VERSION 5.7 ;
  NOWIREEXTENSIONATPIN ON ;
  DIVIDERCHAR "/" ;
  BUSBITCHARS "[]" ;
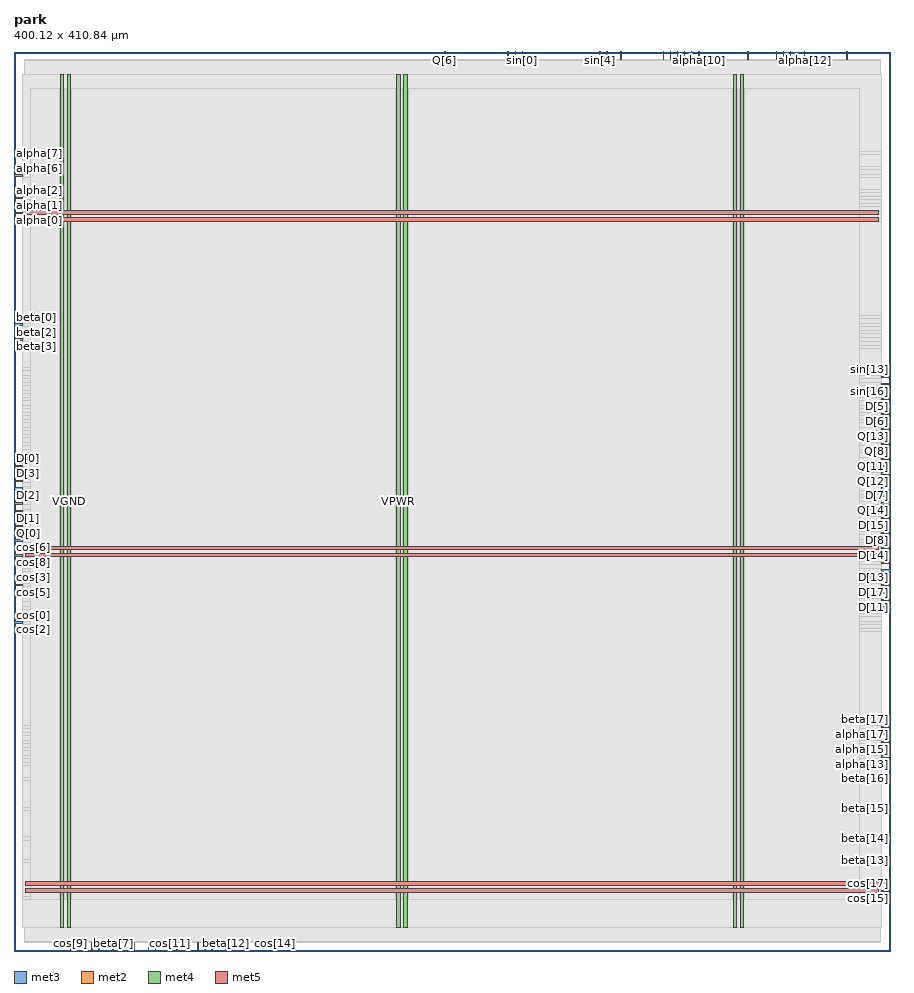
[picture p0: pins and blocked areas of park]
MACRO park
  CLASS BLOCK ;
  FOREIGN park ;
  ORIGIN 0.000 0.000 ;
  SIZE 400.120 BY 410.840 ;
  PIN D[0]
    DIRECTION OUTPUT ;
    USE SIGNAL ;
    ANTENNADIFFAREA 0.795200 ;
    PORT
      LAYER met3 ;
        RECT 0.000 224.440 4.000 225.040 ;
    END
  END D[0]
  PIN D[10]
    DIRECTION OUTPUT ;
    USE SIGNAL ;
    ANTENNADIFFAREA 0.795200 ;
    PORT
      LAYER met3 ;
        RECT 396.120 200.640 400.120 201.240 ;
    END
  END D[10]
  PIN D[11]
    DIRECTION OUTPUT ;
    USE SIGNAL ;
    ANTENNADIFFAREA 0.795200 ;
    PORT
      LAYER met3 ;
        RECT 396.120 156.440 400.120 157.040 ;
    END
  END D[11]
  PIN D[12]
    DIRECTION OUTPUT ;
    USE SIGNAL ;
    ANTENNADIFFAREA 0.445500 ;
    PORT
      LAYER met3 ;
        RECT 396.120 183.640 400.120 184.240 ;
    END
  END D[12]
  PIN D[13]
    DIRECTION OUTPUT ;
    USE SIGNAL ;
    ANTENNADIFFAREA 0.445500 ;
    PORT
      LAYER met3 ;
        RECT 396.120 170.040 400.120 170.640 ;
    END
  END D[13]
  PIN D[14]
    DIRECTION OUTPUT ;
    USE SIGNAL ;
    ANTENNADIFFAREA 0.795200 ;
    PORT
      LAYER met3 ;
        RECT 396.120 180.240 400.120 180.840 ;
    END
  END D[14]
  PIN D[15]
    DIRECTION OUTPUT ;
    USE SIGNAL ;
    ANTENNADIFFAREA 0.795200 ;
    PORT
      LAYER met3 ;
        RECT 396.120 193.840 400.120 194.440 ;
    END
  END D[15]
  PIN D[16]
    DIRECTION OUTPUT ;
    USE SIGNAL ;
    ANTENNADIFFAREA 0.795200 ;
    PORT
      LAYER met3 ;
        RECT 396.120 176.840 400.120 177.440 ;
    END
  END D[16]
  PIN D[17]
    DIRECTION OUTPUT ;
    USE SIGNAL ;
    ANTENNADIFFAREA 0.445500 ;
    PORT
      LAYER met3 ;
        RECT 396.120 163.240 400.120 163.840 ;
    END
  END D[17]
  PIN D[1]
    DIRECTION OUTPUT ;
    USE SIGNAL ;
    ANTENNADIFFAREA 0.795200 ;
    PORT
      LAYER met3 ;
        RECT 0.000 197.240 4.000 197.840 ;
    END
  END D[1]
  PIN D[2]
    DIRECTION OUTPUT ;
    USE SIGNAL ;
    ANTENNADIFFAREA 0.795200 ;
    PORT
      LAYER met3 ;
        RECT 0.000 207.440 4.000 208.040 ;
    END
  END D[2]
  PIN D[3]
    DIRECTION OUTPUT ;
    USE SIGNAL ;
    ANTENNADIFFAREA 0.795200 ;
    PORT
      LAYER met3 ;
        RECT 0.000 221.040 4.000 221.640 ;
    END
  END D[3]
  PIN D[4]
    DIRECTION OUTPUT ;
    USE SIGNAL ;
    ANTENNADIFFAREA 0.795200 ;
    PORT
      LAYER met3 ;
        RECT 0.000 210.840 4.000 211.440 ;
    END
  END D[4]
  PIN D[5]
    DIRECTION OUTPUT ;
    USE SIGNAL ;
    ANTENNADIFFAREA 0.795200 ;
    PORT
      LAYER met3 ;
        RECT 396.120 248.240 400.120 248.840 ;
    END
  END D[5]
  PIN D[6]
    DIRECTION OUTPUT ;
    USE SIGNAL ;
    ANTENNADIFFAREA 0.795200 ;
    PORT
      LAYER met3 ;
        RECT 396.120 244.840 400.120 245.440 ;
    END
  END D[6]
  PIN D[7]
    DIRECTION OUTPUT ;
    USE SIGNAL ;
    ANTENNADIFFAREA 0.795200 ;
    PORT
      LAYER met3 ;
        RECT 396.120 207.440 400.120 208.040 ;
    END
  END D[7]
  PIN D[8]
    DIRECTION OUTPUT ;
    USE SIGNAL ;
    ANTENNADIFFAREA 0.445500 ;
    PORT
      LAYER met3 ;
        RECT 396.120 190.440 400.120 191.040 ;
    END
  END D[8]
  PIN D[9]
    DIRECTION OUTPUT ;
    USE SIGNAL ;
    ANTENNADIFFAREA 0.795200 ;
    PORT
      LAYER met3 ;
        RECT 396.120 166.640 400.120 167.240 ;
    END
  END D[9]
  PIN Q[0]
    DIRECTION OUTPUT ;
    USE SIGNAL ;
    ANTENNADIFFAREA 0.795200 ;
    PORT
      LAYER met3 ;
        RECT 0.000 193.840 4.000 194.440 ;
    END
  END Q[0]
  PIN Q[10]
    DIRECTION OUTPUT ;
    USE SIGNAL ;
    ANTENNADIFFAREA 0.795200 ;
    PORT
      LAYER met3 ;
        RECT 396.120 217.640 400.120 218.240 ;
    END
  END Q[10]
  PIN Q[11]
    DIRECTION OUTPUT ;
    USE SIGNAL ;
    ANTENNADIFFAREA 0.795200 ;
    PORT
      LAYER met3 ;
        RECT 396.120 221.040 400.120 221.640 ;
    END
  END Q[11]
  PIN Q[12]
    DIRECTION OUTPUT ;
    USE SIGNAL ;
    ANTENNADIFFAREA 0.795200 ;
    PORT
      LAYER met3 ;
        RECT 396.120 214.240 400.120 214.840 ;
    END
  END Q[12]
  PIN Q[13]
    DIRECTION OUTPUT ;
    USE SIGNAL ;
    ANTENNADIFFAREA 0.445500 ;
    PORT
      LAYER met3 ;
        RECT 396.120 238.040 400.120 238.640 ;
    END
  END Q[13]
  PIN Q[14]
    DIRECTION OUTPUT ;
    USE SIGNAL ;
    ANTENNADIFFAREA 0.445500 ;
    PORT
      LAYER met3 ;
        RECT 396.120 204.040 400.120 204.640 ;
    END
  END Q[14]
  PIN Q[15]
    DIRECTION OUTPUT ;
    USE SIGNAL ;
    ANTENNADIFFAREA 0.445500 ;
    PORT
      LAYER met3 ;
        RECT 396.120 210.840 400.120 211.440 ;
    END
  END Q[15]
  PIN Q[16]
    DIRECTION OUTPUT ;
    USE SIGNAL ;
    ANTENNADIFFAREA 0.795200 ;
    PORT
      LAYER met3 ;
        RECT 396.120 187.040 400.120 187.640 ;
    END
  END Q[16]
  PIN Q[17]
    DIRECTION OUTPUT ;
    USE SIGNAL ;
    ANTENNADIFFAREA 0.795200 ;
    PORT
      LAYER met3 ;
        RECT 396.120 173.440 400.120 174.040 ;
    END
  END Q[17]
  PIN Q[1]
    DIRECTION OUTPUT ;
    USE SIGNAL ;
    ANTENNADIFFAREA 0.795200 ;
    PORT
      LAYER met3 ;
        RECT 0.000 204.040 4.000 204.640 ;
    END
  END Q[1]
  PIN Q[2]
    DIRECTION OUTPUT ;
    USE SIGNAL ;
    ANTENNADIFFAREA 0.795200 ;
    PORT
      LAYER met3 ;
        RECT 0.000 217.640 4.000 218.240 ;
    END
  END Q[2]
  PIN Q[3]
    DIRECTION OUTPUT ;
    USE SIGNAL ;
    ANTENNADIFFAREA 0.795200 ;
    PORT
      LAYER met3 ;
        RECT 0.000 200.640 4.000 201.240 ;
    END
  END Q[3]
  PIN Q[4]
    DIRECTION OUTPUT ;
    USE SIGNAL ;
    ANTENNADIFFAREA 0.795200 ;
    PORT
      LAYER met3 ;
        RECT 0.000 190.440 4.000 191.040 ;
    END
  END Q[4]
  PIN Q[5]
    DIRECTION OUTPUT ;
    USE SIGNAL ;
    ANTENNADIFFAREA 0.795200 ;
    PORT
      LAYER met3 ;
        RECT 0.000 214.240 4.000 214.840 ;
    END
  END Q[5]
  PIN Q[6]
    DIRECTION OUTPUT ;
    USE SIGNAL ;
    ANTENNADIFFAREA 0.795200 ;
    PORT
      LAYER met2 ;
        RECT 196.510 406.840 196.790 410.840 ;
    END
  END Q[6]
  PIN Q[7]
    DIRECTION OUTPUT ;
    USE SIGNAL ;
    ANTENNADIFFAREA 0.795200 ;
    PORT
      LAYER met3 ;
        RECT 396.120 241.440 400.120 242.040 ;
    END
  END Q[7]
  PIN Q[8]
    DIRECTION OUTPUT ;
    USE SIGNAL ;
    ANTENNADIFFAREA 0.445500 ;
    PORT
      LAYER met3 ;
        RECT 396.120 231.240 400.120 231.840 ;
    END
  END Q[8]
  PIN Q[9]
    DIRECTION OUTPUT ;
    USE SIGNAL ;
    ANTENNADIFFAREA 0.795200 ;
    PORT
      LAYER met3 ;
        RECT 396.120 234.640 400.120 235.240 ;
    END
  END Q[9]
  PIN VGND
    DIRECTION INOUT ;
    USE GROUND ;
    PORT
      LAYER met4 ;
        RECT 24.340 10.640 25.940 400.080 ;
    END
    PORT
      LAYER met4 ;
        RECT 177.940 10.640 179.540 400.080 ;
    END
    PORT
      LAYER met4 ;
        RECT 331.540 10.640 333.140 400.080 ;
    END
    PORT
      LAYER met5 ;
        RECT 5.280 30.030 394.460 31.630 ;
    END
    PORT
      LAYER met5 ;
        RECT 5.280 183.210 394.460 184.810 ;
    END
    PORT
      LAYER met5 ;
        RECT 5.280 336.390 394.460 337.990 ;
    END
  END VGND
  PIN VPWR
    DIRECTION INOUT ;
    USE POWER ;
    PORT
      LAYER met4 ;
        RECT 21.040 10.640 22.640 400.080 ;
    END
    PORT
      LAYER met4 ;
        RECT 174.640 10.640 176.240 400.080 ;
    END
    PORT
      LAYER met4 ;
        RECT 328.240 10.640 329.840 400.080 ;
    END
    PORT
      LAYER met5 ;
        RECT 5.280 26.730 394.460 28.330 ;
    END
    PORT
      LAYER met5 ;
        RECT 5.280 179.910 394.460 181.510 ;
    END
    PORT
      LAYER met5 ;
        RECT 5.280 333.090 394.460 334.690 ;
    END
  END VPWR
  PIN alpha[0]
    DIRECTION INPUT ;
    USE SIGNAL ;
    ANTENNAGATEAREA 0.159000 ;
    PORT
      LAYER met3 ;
        RECT 0.000 333.240 4.000 333.840 ;
    END
  END alpha[0]
  PIN alpha[10]
    DIRECTION INPUT ;
    USE SIGNAL ;
    ANTENNAGATEAREA 0.196500 ;
    PORT
      LAYER met2 ;
        RECT 312.430 406.840 312.710 410.840 ;
    END
  END alpha[10]
  PIN alpha[11]
    DIRECTION INPUT ;
    USE SIGNAL ;
    ANTENNAGATEAREA 0.196500 ;
    PORT
      LAYER met2 ;
        RECT 334.970 406.840 335.250 410.840 ;
    END
  END alpha[11]
  PIN alpha[12]
    DIRECTION INPUT ;
    USE SIGNAL ;
    ANTENNAGATEAREA 0.247500 ;
    PORT
      LAYER met2 ;
        RECT 360.730 406.840 361.010 410.840 ;
    END
  END alpha[12]
  PIN alpha[13]
    DIRECTION INPUT ;
    USE SIGNAL ;
    ANTENNAGATEAREA 0.247500 ;
    PORT
      LAYER met3 ;
        RECT 396.120 85.040 400.120 85.640 ;
    END
  END alpha[13]
  PIN alpha[14]
    DIRECTION INPUT ;
    USE SIGNAL ;
    ANTENNAGATEAREA 0.196500 ;
    PORT
      LAYER met3 ;
        RECT 396.120 88.440 400.120 89.040 ;
    END
  END alpha[14]
  PIN alpha[15]
    DIRECTION INPUT ;
    USE SIGNAL ;
    ANTENNAGATEAREA 0.196500 ;
    PORT
      LAYER met3 ;
        RECT 396.120 91.840 400.120 92.440 ;
    END
  END alpha[15]
  PIN alpha[16]
    DIRECTION INPUT ;
    USE SIGNAL ;
    ANTENNAGATEAREA 0.213000 ;
    PORT
      LAYER met3 ;
        RECT 396.120 95.240 400.120 95.840 ;
    END
  END alpha[16]
  PIN alpha[17]
    DIRECTION INPUT ;
    USE SIGNAL ;
    ANTENNAGATEAREA 0.159000 ;
    PORT
      LAYER met3 ;
        RECT 396.120 98.640 400.120 99.240 ;
    END
  END alpha[17]
  PIN alpha[1]
    DIRECTION INPUT ;
    USE SIGNAL ;
    ANTENNAGATEAREA 0.196500 ;
    PORT
      LAYER met3 ;
        RECT 0.000 340.040 4.000 340.640 ;
    END
  END alpha[1]
  PIN alpha[2]
    DIRECTION INPUT ;
    USE SIGNAL ;
    ANTENNAGATEAREA 0.159000 ;
    PORT
      LAYER met3 ;
        RECT 0.000 343.440 4.000 344.040 ;
    END
  END alpha[2]
  PIN alpha[3]
    DIRECTION INPUT ;
    USE SIGNAL ;
    ANTENNAGATEAREA 0.213000 ;
    PORT
      LAYER met3 ;
        RECT 0.000 336.640 4.000 337.240 ;
    END
  END alpha[3]
  PIN alpha[4]
    DIRECTION INPUT ;
    USE SIGNAL ;
    ANTENNAGATEAREA 0.196500 ;
    PORT
      LAYER met3 ;
        RECT 0.000 346.840 4.000 347.440 ;
    END
  END alpha[4]
  PIN alpha[5]
    DIRECTION INPUT ;
    USE SIGNAL ;
    ANTENNAGATEAREA 0.196500 ;
    PORT
      LAYER met3 ;
        RECT 0.000 353.640 4.000 354.240 ;
    END
  END alpha[5]
  PIN alpha[6]
    DIRECTION INPUT ;
    USE SIGNAL ;
    ANTENNAGATEAREA 0.196500 ;
    PORT
      LAYER met3 ;
        RECT 0.000 357.040 4.000 357.640 ;
    END
  END alpha[6]
  PIN alpha[7]
    DIRECTION INPUT ;
    USE SIGNAL ;
    ANTENNAGATEAREA 0.196500 ;
    PORT
      LAYER met3 ;
        RECT 0.000 363.840 4.000 364.440 ;
    END
  END alpha[7]
  PIN alpha[8]
    DIRECTION INPUT ;
    USE SIGNAL ;
    ANTENNAGATEAREA 0.196500 ;
    PORT
      LAYER met2 ;
        RECT 296.330 406.840 296.610 410.840 ;
    END
  END alpha[8]
  PIN alpha[9]
    DIRECTION INPUT ;
    USE SIGNAL ;
    ANTENNAGATEAREA 0.196500 ;
    PORT
      LAYER met2 ;
        RECT 302.770 406.840 303.050 410.840 ;
    END
  END alpha[9]
  PIN beta[0]
    DIRECTION INPUT ;
    USE SIGNAL ;
    ANTENNAGATEAREA 0.196500 ;
    PORT
      LAYER met3 ;
        RECT 0.000 289.040 4.000 289.640 ;
    END
  END beta[0]
  PIN beta[10]
    DIRECTION INPUT ;
    USE SIGNAL ;
    ANTENNAGATEAREA 0.495000 ;
    PORT
      LAYER met2 ;
        RECT 74.150 0.000 74.430 4.000 ;
    END
  END beta[10]
  PIN beta[11]
    DIRECTION INPUT ;
    USE SIGNAL ;
    ANTENNAGATEAREA 0.196500 ;
    PORT
      LAYER met2 ;
        RECT 87.030 0.000 87.310 4.000 ;
    END
  END beta[11]
  PIN beta[12]
    DIRECTION INPUT ;
    USE SIGNAL ;
    ANTENNAGATEAREA 0.196500 ;
    PORT
      LAYER met2 ;
        RECT 96.690 0.000 96.970 4.000 ;
    END
  END beta[12]
  PIN beta[13]
    DIRECTION INPUT ;
    USE SIGNAL ;
    ANTENNAGATEAREA 0.196500 ;
    PORT
      LAYER met3 ;
        RECT 396.120 40.840 400.120 41.440 ;
    END
  END beta[13]
  PIN beta[14]
    DIRECTION INPUT ;
    USE SIGNAL ;
    ANTENNAGATEAREA 0.196500 ;
    PORT
      LAYER met3 ;
        RECT 396.120 51.040 400.120 51.640 ;
    END
  END beta[14]
  PIN beta[15]
    DIRECTION INPUT ;
    USE SIGNAL ;
    ANTENNAGATEAREA 0.196500 ;
    PORT
      LAYER met3 ;
        RECT 396.120 64.640 400.120 65.240 ;
    END
  END beta[15]
  PIN beta[16]
    DIRECTION INPUT ;
    USE SIGNAL ;
    ANTENNAGATEAREA 0.196500 ;
    PORT
      LAYER met3 ;
        RECT 396.120 78.240 400.120 78.840 ;
    END
  END beta[16]
  PIN beta[17]
    DIRECTION INPUT ;
    USE SIGNAL ;
    ANTENNAGATEAREA 0.213000 ;
    PORT
      LAYER met3 ;
        RECT 396.120 102.040 400.120 102.640 ;
    END
  END beta[17]
  PIN beta[1]
    DIRECTION INPUT ;
    USE SIGNAL ;
    ANTENNAGATEAREA 0.213000 ;
    PORT
      LAYER met3 ;
        RECT 0.000 285.640 4.000 286.240 ;
    END
  END beta[1]
  PIN beta[2]
    DIRECTION INPUT ;
    USE SIGNAL ;
    ANTENNAGATEAREA 0.213000 ;
    PORT
      LAYER met3 ;
        RECT 0.000 282.240 4.000 282.840 ;
    END
  END beta[2]
  PIN beta[3]
    DIRECTION INPUT ;
    USE SIGNAL ;
    ANTENNAGATEAREA 0.196500 ;
    PORT
      LAYER met3 ;
        RECT 0.000 278.840 4.000 279.440 ;
    END
  END beta[3]
  PIN beta[4]
    DIRECTION INPUT ;
    USE SIGNAL ;
    ANTENNAGATEAREA 0.196500 ;
    PORT
      LAYER met3 ;
        RECT 0.000 275.440 4.000 276.040 ;
    END
  END beta[4]
  PIN beta[5]
    DIRECTION INPUT ;
    USE SIGNAL ;
    ANTENNAGATEAREA 0.213000 ;
    PORT
      LAYER met2 ;
        RECT 35.510 0.000 35.790 4.000 ;
    END
  END beta[5]
  PIN beta[6]
    DIRECTION INPUT ;
    USE SIGNAL ;
    ANTENNAGATEAREA 0.196500 ;
    PORT
      LAYER met2 ;
        RECT 38.730 0.000 39.010 4.000 ;
    END
  END beta[6]
  PIN beta[7]
    DIRECTION INPUT ;
    USE SIGNAL ;
    ANTENNAGATEAREA 0.213000 ;
    PORT
      LAYER met2 ;
        RECT 45.170 0.000 45.450 4.000 ;
    END
  END beta[7]
  PIN beta[8]
    DIRECTION INPUT ;
    USE SIGNAL ;
    ANTENNAGATEAREA 0.990000 ;
    PORT
      LAYER met2 ;
        RECT 54.830 0.000 55.110 4.000 ;
    END
  END beta[8]
  PIN beta[9]
    DIRECTION INPUT ;
    USE SIGNAL ;
    ANTENNAGATEAREA 0.213000 ;
    PORT
      LAYER met2 ;
        RECT 64.490 0.000 64.770 4.000 ;
    END
  END beta[9]
  PIN clk
    DIRECTION INPUT ;
    USE SIGNAL ;
    ANTENNAGATEAREA 0.852000 ;
    PORT
      LAYER met3 ;
        RECT 396.120 227.840 400.120 228.440 ;
    END
  END clk
  PIN cos[0]
    DIRECTION INPUT ;
    USE SIGNAL ;
    ANTENNAGATEAREA 0.196500 ;
    PORT
      LAYER met3 ;
        RECT 0.000 153.040 4.000 153.640 ;
    END
  END cos[0]
  PIN cos[10]
    DIRECTION INPUT ;
    USE SIGNAL ;
    ANTENNAGATEAREA 0.196500 ;
    PORT
      LAYER met2 ;
        RECT 61.270 0.000 61.550 4.000 ;
    END
  END cos[10]
  PIN cos[11]
    DIRECTION INPUT ;
    USE SIGNAL ;
    ANTENNAGATEAREA 0.196500 ;
    PORT
      LAYER met2 ;
        RECT 70.930 0.000 71.210 4.000 ;
    END
  END cos[11]
  PIN cos[12]
    DIRECTION INPUT ;
    USE SIGNAL ;
    ANTENNAGATEAREA 0.196500 ;
    PORT
      LAYER met2 ;
        RECT 83.810 0.000 84.090 4.000 ;
    END
  END cos[12]
  PIN cos[13]
    DIRECTION INPUT ;
    USE SIGNAL ;
    ANTENNAGATEAREA 0.196500 ;
    PORT
      LAYER met2 ;
        RECT 90.250 0.000 90.530 4.000 ;
    END
  END cos[13]
  PIN cos[14]
    DIRECTION INPUT ;
    USE SIGNAL ;
    ANTENNAGATEAREA 0.196500 ;
    PORT
      LAYER met2 ;
        RECT 119.230 0.000 119.510 4.000 ;
    END
  END cos[14]
  PIN cos[15]
    DIRECTION INPUT ;
    USE SIGNAL ;
    ANTENNAGATEAREA 0.196500 ;
    PORT
      LAYER met3 ;
        RECT 396.120 23.840 400.120 24.440 ;
    END
  END cos[15]
  PIN cos[16]
    DIRECTION INPUT ;
    USE SIGNAL ;
    ANTENNAGATEAREA 0.213000 ;
    PORT
      LAYER met3 ;
        RECT 396.120 27.240 400.120 27.840 ;
    END
  END cos[16]
  PIN cos[17]
    DIRECTION INPUT ;
    USE SIGNAL ;
    ANTENNAGATEAREA 0.213000 ;
    PORT
      LAYER met3 ;
        RECT 396.120 30.640 400.120 31.240 ;
    END
  END cos[17]
  PIN cos[1]
    DIRECTION INPUT ;
    USE SIGNAL ;
    ANTENNAGATEAREA 0.196500 ;
    PORT
      LAYER met3 ;
        RECT 0.000 149.640 4.000 150.240 ;
    END
  END cos[1]
  PIN cos[2]
    DIRECTION INPUT ;
    USE SIGNAL ;
    ANTENNAGATEAREA 0.196500 ;
    PORT
      LAYER met3 ;
        RECT 0.000 146.240 4.000 146.840 ;
    END
  END cos[2]
  PIN cos[3]
    DIRECTION INPUT ;
    USE SIGNAL ;
    ANTENNAGATEAREA 0.196500 ;
    PORT
      LAYER met3 ;
        RECT 0.000 170.040 4.000 170.640 ;
    END
  END cos[3]
  PIN cos[4]
    DIRECTION INPUT ;
    USE SIGNAL ;
    ANTENNAGATEAREA 0.213000 ;
    PORT
      LAYER met3 ;
        RECT 0.000 166.640 4.000 167.240 ;
    END
  END cos[4]
  PIN cos[5]
    DIRECTION INPUT ;
    USE SIGNAL ;
    ANTENNAGATEAREA 0.159000 ;
    PORT
      LAYER met3 ;
        RECT 0.000 163.240 4.000 163.840 ;
    END
  END cos[5]
  PIN cos[6]
    DIRECTION INPUT ;
    USE SIGNAL ;
    ANTENNAGATEAREA 0.196500 ;
    PORT
      LAYER met3 ;
        RECT 0.000 187.040 4.000 187.640 ;
    END
  END cos[6]
  PIN cos[7]
    DIRECTION INPUT ;
    USE SIGNAL ;
    ANTENNAGATEAREA 0.196500 ;
    PORT
      LAYER met3 ;
        RECT 0.000 183.640 4.000 184.240 ;
    END
  END cos[7]
  PIN cos[8]
    DIRECTION INPUT ;
    USE SIGNAL ;
    ANTENNAGATEAREA 0.213000 ;
    PORT
      LAYER met3 ;
        RECT 0.000 180.240 4.000 180.840 ;
    END
  END cos[8]
  PIN cos[9]
    DIRECTION INPUT ;
    USE SIGNAL ;
    ANTENNAGATEAREA 0.196500 ;
    PORT
      LAYER met2 ;
        RECT 25.850 0.000 26.130 4.000 ;
    END
  END cos[9]
  PIN done
    DIRECTION OUTPUT ;
    USE SIGNAL ;
    ANTENNADIFFAREA 0.445500 ;
    PORT
      LAYER met3 ;
        RECT 396.120 224.440 400.120 225.040 ;
    END
  END done
  PIN rstb
    DIRECTION INPUT ;
    USE SIGNAL ;
    ANTENNAGATEAREA 0.196500 ;
    PORT
      LAYER met3 ;
        RECT 396.120 159.840 400.120 160.440 ;
    END
  END rstb
  PIN sin[0]
    DIRECTION INPUT ;
    USE SIGNAL ;
    ANTENNAGATEAREA 0.196500 ;
    PORT
      LAYER met2 ;
        RECT 231.930 406.840 232.210 410.840 ;
    END
  END sin[0]
  PIN sin[10]
    DIRECTION INPUT ;
    USE SIGNAL ;
    ANTENNAGATEAREA 0.196500 ;
    PORT
      LAYER met2 ;
        RECT 347.850 406.840 348.130 410.840 ;
    END
  END sin[10]
  PIN sin[11]
    DIRECTION INPUT ;
    USE SIGNAL ;
    ANTENNAGATEAREA 0.196500 ;
    PORT
      LAYER met2 ;
        RECT 354.290 406.840 354.570 410.840 ;
    END
  END sin[11]
  PIN sin[12]
    DIRECTION INPUT ;
    USE SIGNAL ;
    ANTENNAGATEAREA 0.196500 ;
    PORT
      LAYER met3 ;
        RECT 396.120 261.840 400.120 262.440 ;
    END
  END sin[12]
  PIN sin[13]
    DIRECTION INPUT ;
    USE SIGNAL ;
    ANTENNAGATEAREA 0.196500 ;
    PORT
      LAYER met3 ;
        RECT 396.120 265.240 400.120 265.840 ;
    END
  END sin[13]
  PIN sin[14]
    DIRECTION INPUT ;
    USE SIGNAL ;
    ANTENNAGATEAREA 0.159000 ;
    PORT
      LAYER met2 ;
        RECT 380.050 406.840 380.330 410.840 ;
    END
  END sin[14]
  PIN sin[15]
    DIRECTION INPUT ;
    USE SIGNAL ;
    ANTENNAGATEAREA 0.126000 ;
    PORT
      LAYER met3 ;
        RECT 396.120 251.640 400.120 252.240 ;
    END
  END sin[15]
  PIN sin[16]
    DIRECTION INPUT ;
    USE SIGNAL ;
    ANTENNAGATEAREA 0.126000 ;
    PORT
      LAYER met3 ;
        RECT 396.120 255.040 400.120 255.640 ;
    END
  END sin[16]
  PIN sin[17]
    DIRECTION INPUT ;
    USE SIGNAL ;
    ANTENNAGATEAREA 0.159000 ;
    PORT
      LAYER met3 ;
        RECT 396.120 258.440 400.120 259.040 ;
    END
  END sin[17]
  PIN sin[1]
    DIRECTION INPUT ;
    USE SIGNAL ;
    ANTENNAGATEAREA 0.196500 ;
    PORT
      LAYER met2 ;
        RECT 228.710 406.840 228.990 410.840 ;
    END
  END sin[1]
  PIN sin[2]
    DIRECTION INPUT ;
    USE SIGNAL ;
    ANTENNAGATEAREA 0.213000 ;
    PORT
      LAYER met2 ;
        RECT 225.490 406.840 225.770 410.840 ;
    END
  END sin[2]
  PIN sin[3]
    DIRECTION INPUT ;
    USE SIGNAL ;
    ANTENNAGATEAREA 0.196500 ;
    PORT
      LAYER met2 ;
        RECT 270.570 406.840 270.850 410.840 ;
    END
  END sin[3]
  PIN sin[4]
    DIRECTION INPUT ;
    USE SIGNAL ;
    ANTENNAGATEAREA 0.196500 ;
    PORT
      LAYER met2 ;
        RECT 267.350 406.840 267.630 410.840 ;
    END
  END sin[4]
  PIN sin[5]
    DIRECTION INPUT ;
    USE SIGNAL ;
    ANTENNAGATEAREA 0.196500 ;
    PORT
      LAYER met2 ;
        RECT 277.010 406.840 277.290 410.840 ;
    END
  END sin[5]
  PIN sin[6]
    DIRECTION INPUT ;
    USE SIGNAL ;
    ANTENNAGATEAREA 0.196500 ;
    PORT
      LAYER met2 ;
        RECT 309.210 406.840 309.490 410.840 ;
    END
  END sin[6]
  PIN sin[7]
    DIRECTION INPUT ;
    USE SIGNAL ;
    ANTENNAGATEAREA 0.196500 ;
    PORT
      LAYER met2 ;
        RECT 305.990 406.840 306.270 410.840 ;
    END
  END sin[7]
  PIN sin[8]
    DIRECTION INPUT ;
    USE SIGNAL ;
    ANTENNAGATEAREA 0.196500 ;
    PORT
      LAYER met2 ;
        RECT 299.550 406.840 299.830 410.840 ;
    END
  END sin[8]
  PIN sin[9]
    DIRECTION INPUT ;
    USE SIGNAL ;
    ANTENNAGATEAREA 0.213000 ;
    PORT
      LAYER met2 ;
        RECT 351.070 406.840 351.350 410.840 ;
    END
  END sin[9]
  PIN start
    DIRECTION INPUT ;
    USE SIGNAL ;
    ANTENNAGATEAREA 0.196500 ;
    PORT
      LAYER met3 ;
        RECT 396.120 197.240 400.120 197.840 ;
    END
  END start
  OBS
      LAYER li1 ;
        RECT 5.520 10.795 394.220 399.925 ;
      LAYER met1 ;
        RECT 4.670 10.640 395.530 400.080 ;
      LAYER met2 ;
        RECT 4.690 406.560 196.230 406.840 ;
        RECT 197.070 406.560 225.210 406.840 ;
        RECT 226.050 406.560 228.430 406.840 ;
        RECT 229.270 406.560 231.650 406.840 ;
        RECT 232.490 406.560 267.070 406.840 ;
        RECT 267.910 406.560 270.290 406.840 ;
        RECT 271.130 406.560 276.730 406.840 ;
        RECT 277.570 406.560 296.050 406.840 ;
        RECT 296.890 406.560 299.270 406.840 ;
        RECT 300.110 406.560 302.490 406.840 ;
        RECT 303.330 406.560 305.710 406.840 ;
        RECT 306.550 406.560 308.930 406.840 ;
        RECT 309.770 406.560 312.150 406.840 ;
        RECT 312.990 406.560 334.690 406.840 ;
        RECT 335.530 406.560 347.570 406.840 ;
        RECT 348.410 406.560 350.790 406.840 ;
        RECT 351.630 406.560 354.010 406.840 ;
        RECT 354.850 406.560 360.450 406.840 ;
        RECT 361.290 406.560 379.770 406.840 ;
        RECT 380.610 406.560 395.510 406.840 ;
        RECT 4.690 4.280 395.510 406.560 ;
        RECT 4.690 4.000 25.570 4.280 ;
        RECT 26.410 4.000 35.230 4.280 ;
        RECT 36.070 4.000 38.450 4.280 ;
        RECT 39.290 4.000 44.890 4.280 ;
        RECT 45.730 4.000 54.550 4.280 ;
        RECT 55.390 4.000 60.990 4.280 ;
        RECT 61.830 4.000 64.210 4.280 ;
        RECT 65.050 4.000 70.650 4.280 ;
        RECT 71.490 4.000 73.870 4.280 ;
        RECT 74.710 4.000 83.530 4.280 ;
        RECT 84.370 4.000 86.750 4.280 ;
        RECT 87.590 4.000 89.970 4.280 ;
        RECT 90.810 4.000 96.410 4.280 ;
        RECT 97.250 4.000 118.950 4.280 ;
        RECT 119.790 4.000 395.510 4.280 ;
      LAYER met3 ;
        RECT 3.990 364.840 396.120 400.005 ;
        RECT 4.400 363.440 396.120 364.840 ;
        RECT 3.990 358.040 396.120 363.440 ;
        RECT 4.400 356.640 396.120 358.040 ;
        RECT 3.990 354.640 396.120 356.640 ;
        RECT 4.400 353.240 396.120 354.640 ;
        RECT 3.990 347.840 396.120 353.240 ;
        RECT 4.400 346.440 396.120 347.840 ;
        RECT 3.990 344.440 396.120 346.440 ;
        RECT 4.400 343.040 396.120 344.440 ;
        RECT 3.990 341.040 396.120 343.040 ;
        RECT 4.400 339.640 396.120 341.040 ;
        RECT 3.990 337.640 396.120 339.640 ;
        RECT 4.400 336.240 396.120 337.640 ;
        RECT 3.990 334.240 396.120 336.240 ;
        RECT 4.400 332.840 396.120 334.240 ;
        RECT 3.990 290.040 396.120 332.840 ;
        RECT 4.400 288.640 396.120 290.040 ;
        RECT 3.990 286.640 396.120 288.640 ;
        RECT 4.400 285.240 396.120 286.640 ;
        RECT 3.990 283.240 396.120 285.240 ;
        RECT 4.400 281.840 396.120 283.240 ;
        RECT 3.990 279.840 396.120 281.840 ;
        RECT 4.400 278.440 396.120 279.840 ;
        RECT 3.990 276.440 396.120 278.440 ;
        RECT 4.400 275.040 396.120 276.440 ;
        RECT 3.990 266.240 396.120 275.040 ;
        RECT 3.990 264.840 395.720 266.240 ;
        RECT 3.990 262.840 396.120 264.840 ;
        RECT 3.990 261.440 395.720 262.840 ;
        RECT 3.990 259.440 396.120 261.440 ;
        RECT 3.990 258.040 395.720 259.440 ;
        RECT 3.990 256.040 396.120 258.040 ;
        RECT 3.990 254.640 395.720 256.040 ;
        RECT 3.990 252.640 396.120 254.640 ;
        RECT 3.990 251.240 395.720 252.640 ;
        RECT 3.990 249.240 396.120 251.240 ;
        RECT 3.990 247.840 395.720 249.240 ;
        RECT 3.990 245.840 396.120 247.840 ;
        RECT 3.990 244.440 395.720 245.840 ;
        RECT 3.990 242.440 396.120 244.440 ;
        RECT 3.990 241.040 395.720 242.440 ;
        RECT 3.990 239.040 396.120 241.040 ;
        RECT 3.990 237.640 395.720 239.040 ;
        RECT 3.990 235.640 396.120 237.640 ;
        RECT 3.990 234.240 395.720 235.640 ;
        RECT 3.990 232.240 396.120 234.240 ;
        RECT 3.990 230.840 395.720 232.240 ;
        RECT 3.990 228.840 396.120 230.840 ;
        RECT 3.990 227.440 395.720 228.840 ;
        RECT 3.990 225.440 396.120 227.440 ;
        RECT 4.400 224.040 395.720 225.440 ;
        RECT 3.990 222.040 396.120 224.040 ;
        RECT 4.400 220.640 395.720 222.040 ;
        RECT 3.990 218.640 396.120 220.640 ;
        RECT 4.400 217.240 395.720 218.640 ;
        RECT 3.990 215.240 396.120 217.240 ;
        RECT 4.400 213.840 395.720 215.240 ;
        RECT 3.990 211.840 396.120 213.840 ;
        RECT 4.400 210.440 395.720 211.840 ;
        RECT 3.990 208.440 396.120 210.440 ;
        RECT 4.400 207.040 395.720 208.440 ;
        RECT 3.990 205.040 396.120 207.040 ;
        RECT 4.400 203.640 395.720 205.040 ;
        RECT 3.990 201.640 396.120 203.640 ;
        RECT 4.400 200.240 395.720 201.640 ;
        RECT 3.990 198.240 396.120 200.240 ;
        RECT 4.400 196.840 395.720 198.240 ;
        RECT 3.990 194.840 396.120 196.840 ;
        RECT 4.400 193.440 395.720 194.840 ;
        RECT 3.990 191.440 396.120 193.440 ;
        RECT 4.400 190.040 395.720 191.440 ;
        RECT 3.990 188.040 396.120 190.040 ;
        RECT 4.400 186.640 395.720 188.040 ;
        RECT 3.990 184.640 396.120 186.640 ;
        RECT 4.400 183.240 395.720 184.640 ;
        RECT 3.990 181.240 396.120 183.240 ;
        RECT 4.400 179.840 395.720 181.240 ;
        RECT 3.990 177.840 396.120 179.840 ;
        RECT 3.990 176.440 395.720 177.840 ;
        RECT 3.990 174.440 396.120 176.440 ;
        RECT 3.990 173.040 395.720 174.440 ;
        RECT 3.990 171.040 396.120 173.040 ;
        RECT 4.400 169.640 395.720 171.040 ;
        RECT 3.990 167.640 396.120 169.640 ;
        RECT 4.400 166.240 395.720 167.640 ;
        RECT 3.990 164.240 396.120 166.240 ;
        RECT 4.400 162.840 395.720 164.240 ;
        RECT 3.990 160.840 396.120 162.840 ;
        RECT 3.990 159.440 395.720 160.840 ;
        RECT 3.990 157.440 396.120 159.440 ;
        RECT 3.990 156.040 395.720 157.440 ;
        RECT 3.990 154.040 396.120 156.040 ;
        RECT 4.400 152.640 396.120 154.040 ;
        RECT 3.990 150.640 396.120 152.640 ;
        RECT 4.400 149.240 396.120 150.640 ;
        RECT 3.990 147.240 396.120 149.240 ;
        RECT 4.400 145.840 396.120 147.240 ;
        RECT 3.990 103.040 396.120 145.840 ;
        RECT 3.990 101.640 395.720 103.040 ;
        RECT 3.990 99.640 396.120 101.640 ;
        RECT 3.990 98.240 395.720 99.640 ;
        RECT 3.990 96.240 396.120 98.240 ;
        RECT 3.990 94.840 395.720 96.240 ;
        RECT 3.990 92.840 396.120 94.840 ;
        RECT 3.990 91.440 395.720 92.840 ;
        RECT 3.990 89.440 396.120 91.440 ;
        RECT 3.990 88.040 395.720 89.440 ;
        RECT 3.990 86.040 396.120 88.040 ;
        RECT 3.990 84.640 395.720 86.040 ;
        RECT 3.990 79.240 396.120 84.640 ;
        RECT 3.990 77.840 395.720 79.240 ;
        RECT 3.990 65.640 396.120 77.840 ;
        RECT 3.990 64.240 395.720 65.640 ;
        RECT 3.990 52.040 396.120 64.240 ;
        RECT 3.990 50.640 395.720 52.040 ;
        RECT 3.990 41.840 396.120 50.640 ;
        RECT 3.990 40.440 395.720 41.840 ;
        RECT 3.990 31.640 396.120 40.440 ;
        RECT 3.990 30.240 395.720 31.640 ;
        RECT 3.990 28.240 396.120 30.240 ;
        RECT 3.990 26.840 395.720 28.240 ;
        RECT 3.990 24.840 396.120 26.840 ;
        RECT 3.990 23.440 395.720 24.840 ;
        RECT 3.990 10.715 396.120 23.440 ;
      LAYER met4 ;
        RECT 7.655 23.295 20.640 393.545 ;
        RECT 23.040 23.295 23.940 393.545 ;
        RECT 26.340 23.295 174.240 393.545 ;
        RECT 176.640 23.295 177.540 393.545 ;
        RECT 179.940 23.295 327.840 393.545 ;
        RECT 330.240 23.295 331.140 393.545 ;
        RECT 333.540 23.295 386.105 393.545 ;
  END
END park
END LIBRARY

